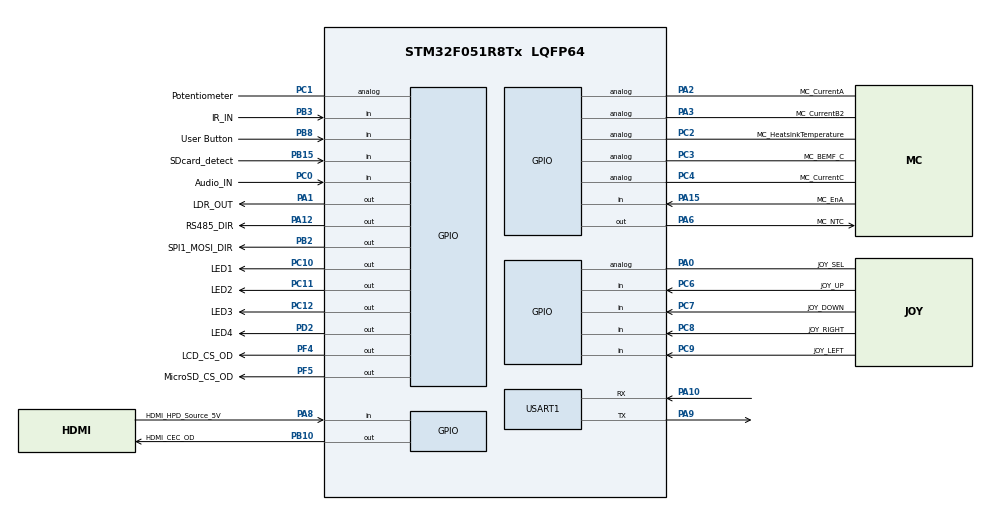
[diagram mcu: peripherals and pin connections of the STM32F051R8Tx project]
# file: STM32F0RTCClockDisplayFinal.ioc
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Mcu.Family=STM32F0
Mcu.Name=STM32F051R8Tx
Mcu.Package=LQFP64
PA0.GPIO_Label=JOY_SEL
PA0.Signal=GPIO_Analog
PA1.GPIO_Label=LDR_OUT
PA1.Signal=GPIO_Output
PA10.Mode=Asynchronous
PA10.Signal=USART1_RX
PA11.Signal=USART1_CTS
PA12.GPIO_Label=RS485_DIR
PA12.Signal=GPIO_Output
PA13.Mode=Serial_Wire
PA13.Signal=SYS_SWDIO
PA14.Mode=Serial_Wire
PA14.Signal=SYS_SWCLK
PA15.GPIO_Label=MC_EnA
PA15.Signal=GPIO_Input
PA2.GPIO_Label=MC_CurrentA
PA2.Signal=GPIO_Analog
PA3.GPIO_Label=MC_CurrentB2
PA3.Signal=GPIO_Analog
PA4.GPIO_Label=Audio_OUT
PA4.Signal=COMP_DAC11_group
PA5.Signal=SPI1_SCK
PA6.GPIO_Label=MC_NTC
PA6.Signal=GPIO_Output
PA7.Signal=SPI1_MOSI
PA8.GPIO_Label=HDMI_HPD_Source_5V
PA8.Signal=GPIO_Input
PA9.Mode=Asynchronous
PA9.Signal=USART1_TX
PB0.Signal=TSC_G3_IO2
PB1.GPIO_Label=MC_PFCpwm
PB1.Signal=S_TIM3_CH4
PB10.GPIO_Label=HDMI_CEC_OD
PB10.Signal=GPIO_Output
PB11.Signal=TSC_G6_IO1
PB12.Signal=TSC_G6_IO2
PB13.Signal=TSC_G6_IO3
PB14.Signal=TSC_G6_IO4
PB15.GPIO_Label=SDcard_detect
PB15.Signal=GPIO_Input
PB2.GPIO_Label=SPI1_MOSI_DIR
PB2.Signal=GPIO_Output
PB3.GPIO_Label=IR_IN
PB3.Signal=GPIO_Input
PB4.Signal=SPI1_MISO
PB5.GPIO_Pu=GPIO_PULLUP
PB5.Signal=I2C1_SMBA
PB8.GPIO_Label=User Button
PB8.Signal=GPIO_Input
PB9.Signal=IR_OUT
PC0.GPIO_Label=Audio_IN
PC0.Signal=GPIO_Input
PC1.GPIO_Label=Potentiometer
PC1.Signal=GPIO_Analog
PC10.GPIO_Label=LED1
PC10.Signal=GPIO_Output
PC11.GPIO_Label=LED2
PC11.Signal=GPIO_Output
PC12.GPIO_Label=LED3
PC12.Signal=GPIO_Output
PC13.Signal=SYS_WKUP2
PC14-OSC32_IN.Mode=LSE-External-Oscillator
PC14-OSC32_IN.Signal=RCC_OSC32_IN
PC15-OSC32_OUT.Mode=LSE-External-Oscillator
PC15-OSC32_OUT.Signal=RCC_OSC32_OUT
PC2.GPIO_Label=MC_HeatsinkTemperature
PC2.Signal=GPIO_Analog
PC3.GPIO_Label=MC_BEMF_C
PC3.Signal=GPIO_Analog
PC4.GPIO_Label=MC_CurrentC
PC4.Signal=GPIO_Analog
PC5.Signal=TSC_G3_IO1
PC6.GPIO_Label=JOY_UP
PC6.Signal=GPIO_Input
PC7.GPIO_Label=JOY_DOWN
PC7.Signal=GPIO_Input
PC8.GPIO_Label=JOY_RIGHT
PC8.Signal=GPIO_Input
PC9.GPIO_Label=JOY_LEFT
PC9.Signal=GPIO_Input
PD2.GPIO_Label=LED4
PD2.Signal=GPIO_Output
PF0-OSC_IN.Mode=HSE-External-Oscillator
PF0-OSC_IN.Signal=RCC_OSC_IN
PF1-OSC_OUT.Mode=HSE-External-Oscillator
PF1-OSC_OUT.Signal=RCC_OSC_OUT
PF4.GPIO_Label=LCD_CS_OD
PF4.Signal=GPIO_Output
PF5.GPIO_Label=MicroSD_CS_OD
PF5.Signal=GPIO_Output
PF7.GPIO_Pu=GPIO_PULLUP
PF7.Signal=I2C2_SDA
ProjectManager.HeapSize=0x200
ProjectManager.StackSize=0x400
ProjectManager.TargetToolchain=STM32CubeIDE
RCC.AHBCLKDivider=RCC_SYSCLK_DIV2
RCC.AHBFreq_Value=8000000
RCC.APB1Freq_Value=8000000
RCC.APB1TimFreq_Value=8000000
RCC.HCLKFreq_Value=8000000
RCC.PLLMUL=RCC_PLL_MUL4
RCC.SYSCLKFreq_VALUE=16000000
RCC.SYSCLKSource=RCC_SYSCLKSOURCE_PLLCLK
RTC.Month=RTC_MONTH_APRIL
RTC.Year=23
SH.COMP_DAC11_group.0=DAC1_OUT1
SH.S_TIM3_CH4.0=TIM3_CH4
USART1.VirtualMode-Asynchronous=VM_ASYNC
VP_RTC_VS_RTC_Activate.Mode=RTC_Enabled
VP_RTC_VS_RTC_Calendar.Mode=RTC_Calendar
board=STM320518-EVAL

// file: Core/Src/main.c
/* USER CODE BEGIN Header */
/**
  ******************************************************************************
  * @file           : main.c
  * @brief          : Main program body
  ******************************************************************************
  * @attention
  *
  * Copyright (c) 2023 STMicroelectronics.
  * All rights reserved.
  *
  * This software is licensed under terms that can be found in the LICENSE file
  * in the root directory of this software component.
  * If no LICENSE file comes with this software, it is provided AS-IS.
  *
  ******************************************************************************
  */
/* USER CODE END Header */
#include "main.h"

/* USER CODE BEGIN Includes */
#include <stdio.h>
#include <string.h>
/* USER CODE END Includes */

/* USER CODE BEGIN PTD */
char time[30];
char date[30];
/* USER CODE END PTD */
RTC_TimeTypeDef sTime;
  RTC_DateTypeDef sDate;

RTC_HandleTypeDef hrtc;

UART_HandleTypeDef huart1;

void SystemClock_Config(void);
static void MX_GPIO_Init(void);
static void MX_RTC_Init(void);
static void MX_USART1_UART_Init(void);

int main(void)
{

  /* MCU Configuration--------------------------------------------------------*/

  /* Reset of all peripherals, Initializes the Flash interface and the Systick. */
  HAL_Init();

  /* Configure the system clock */
  SystemClock_Config();

  /* Initialize all configured peripherals */
  MX_GPIO_Init();
  MX_RTC_Init();
  MX_USART1_UART_Init();

  /* Infinite loop */
  while (1)
  {
HAL_RTC_GetDate(&hrtc, &sDate, RTC_FORMAT_BIN);
HAL_RTC_GetTime(&hrtc, &sTime, RTC_FORMAT_BIN);

    /* USER CODE BEGIN 3 */
sprintf(time,"Current Time: %02d.%02d.%02d.%02lu\r\n",sTime.Hours,sTime.Minutes,sTime.Seconds, sTime.SubSeconds);

HAL_UART_Transmit(&huart1, (uint8_t *)date, sizeof(date), 300);
HAL_UART_Transmit(&huart1, (uint8_t *)time, sizeof(time), 300);
HAL_Delay(1000);
  }
  /* USER CODE END 3 */
}

void SystemClock_Config(void)
{
  RCC_OscInitTypeDef RCC_OscInitStruct = {0};
  RCC_ClkInitTypeDef RCC_ClkInitStruct = {0};
  RCC_PeriphCLKInitTypeDef PeriphClkInit = {0};

  /** Initializes the RCC Oscillators according to the specified parameters
  * in the RCC_OscInitTypeDef structure.
  */
  RCC_OscInitStruct.OscillatorType = RCC_OSCILLATORTYPE_HSI|RCC_OSCILLATORTYPE_LSI;
  RCC_OscInitStruct.HSIState = RCC_HSI_ON;
  RCC_OscInitStruct.HSICalibrationValue = RCC_HSICALIBRATION_DEFAULT;
  RCC_OscInitStruct.LSIState = RCC_LSI_ON;
  RCC_OscInitStruct.PLL.PLLState = RCC_PLL_ON;
  RCC_OscInitStruct.PLL.PLLSource = RCC_PLLSOURCE_HSI;
  RCC_OscInitStruct.PLL.PLLMUL = RCC_PLL_MUL12;
  RCC_OscInitStruct.PLL.PREDIV = RCC_PREDIV_DIV1;
  if (HAL_RCC_OscConfig(&RCC_OscInitStruct) != HAL_OK)
  {
    Error_Handler();
  }

  /** Initializes the CPU, AHB and APB buses clocks
  */
  RCC_ClkInitStruct.ClockType = RCC_CLOCKTYPE_HCLK|RCC_CLOCKTYPE_SYSCLK
                              |RCC_CLOCKTYPE_PCLK1;
  RCC_ClkInitStruct.SYSCLKSource = RCC_SYSCLKSOURCE_PLLCLK;
  RCC_ClkInitStruct.AHBCLKDivider = RCC_SYSCLK_DIV1;
  RCC_ClkInitStruct.APB1CLKDivider = RCC_HCLK_DIV1;

  if (HAL_RCC_ClockConfig(&RCC_ClkInitStruct, FLASH_LATENCY_1) != HAL_OK)
  {
    Error_Handler();
  }
  PeriphClkInit.PeriphClockSelection = RCC_PERIPHCLK_USART1|RCC_PERIPHCLK_RTC;
  PeriphClkInit.Usart1ClockSelection = RCC_USART1CLKSOURCE_PCLK1;
  PeriphClkInit.RTCClockSelection = RCC_RTCCLKSOURCE_LSI;
  if (HAL_RCCEx_PeriphCLKConfig(&PeriphClkInit) != HAL_OK)
  {
    Error_Handler();
  }
}

static void MX_RTC_Init(void)
{

  RTC_TimeTypeDef sTime = {0};
  RTC_DateTypeDef sDate = {0};

  /** Initialize RTC Only
  */
  hrtc.Instance = RTC;
  hrtc.Init.HourFormat = RTC_HOURFORMAT_24;
  hrtc.Init.AsynchPrediv = 127;
  hrtc.Init.SynchPrediv = 255;
  hrtc.Init.OutPut = RTC_OUTPUT_DISABLE;
  hrtc.Init.OutPutPolarity = RTC_OUTPUT_POLARITY_HIGH;
  hrtc.Init.OutPutType = RTC_OUTPUT_TYPE_OPENDRAIN;
  if (HAL_RTC_Init(&hrtc) != HAL_OK)
  {
    Error_Handler();
  }

  /** Initialize RTC and set the Time and Date
  */
  sTime.Hours = 0x10;
  sTime.Minutes = 0x20;
  sTime.Seconds = 0x30;
  sTime.SubSeconds = 0x40;
  sTime.DayLightSaving = RTC_DAYLIGHTSAVING_NONE;
  sTime.StoreOperation = RTC_STOREOPERATION_RESET;
  if (HAL_RTC_SetTime(&hrtc, &sTime, RTC_FORMAT_BCD) != HAL_OK)
  {
    Error_Handler();
  }
  sDate.WeekDay = RTC_WEEKDAY_MONDAY;
  sDate.Month = RTC_MONTH_APRIL;
  sDate.Date = 0x1;
  sDate.Year = 0x23;

  if (HAL_RTC_SetDate(&hrtc, &sDate, RTC_FORMAT_BCD) != HAL_OK)
  {
    Error_Handler();
  }

}

static void MX_USART1_UART_Init(void)
{

  huart1.Instance = USART1;
  huart1.Init.BaudRate = 115200;
  huart1.Init.WordLength = UART_WORDLENGTH_8B;
  huart1.Init.StopBits = UART_STOPBITS_1;
  huart1.Init.Parity = UART_PARITY_NONE;
  huart1.Init.Mode = UART_MODE_TX_RX;
  huart1.Init.HwFlowCtl = UART_HWCONTROL_NONE;
  huart1.Init.OverSampling = UART_OVERSAMPLING_16;
  huart1.Init.OneBitSampling = UART_ONE_BIT_SAMPLE_DISABLE;
  huart1.AdvancedInit.AdvFeatureInit = UART_ADVFEATURE_NO_INIT;
  if (HAL_UART_Init(&huart1) != HAL_OK)
  {
    Error_Handler();
  }

}

static void MX_GPIO_Init(void)
{
  GPIO_InitTypeDef GPIO_InitStruct = {0};

  /* GPIO Ports Clock Enable */
  __HAL_RCC_GPIOC_CLK_ENABLE();
  __HAL_RCC_GPIOF_CLK_ENABLE();
  __HAL_RCC_GPIOA_CLK_ENABLE();
  __HAL_RCC_GPIOB_CLK_ENABLE();
  __HAL_RCC_GPIOD_CLK_ENABLE();

  /*Configure GPIO pin Output Level */
  HAL_GPIO_WritePin(GPIOA, LDR_OUT_Pin|MC_NTC_Pin|RS485_DIR_Pin, GPIO_PIN_RESET);

  /*Configure GPIO pin Output Level */
  HAL_GPIO_WritePin(GPIOF, LCD_CS_OD_Pin|MicroSD_CS_OD_Pin, GPIO_PIN_RESET);

  /*Configure GPIO pin Output Level */
  HAL_GPIO_WritePin(GPIOB, SPI1_MOSI_DIR_Pin|HDMI_CEC_OD_Pin, GPIO_PIN_RESET);

  /*Configure GPIO pin Output Level */
  HAL_GPIO_WritePin(GPIOC, LED1_Pin|LED2_Pin|LED3_Pin, GPIO_PIN_RESET);

  /*Configure GPIO pin Output Level */
  HAL_GPIO_WritePin(LED4_GPIO_Port, LED4_Pin, GPIO_PIN_RESET);

  /*Configure GPIO pins : Audio_IN_Pin JOY_UP_Pin JOY_DOWN_Pin JOY_RIGHT_Pin
                           JOY_LEFT_Pin */
  GPIO_InitStruct.Pin = Audio_IN_Pin|JOY_UP_Pin|JOY_DOWN_Pin|JOY_RIGHT_Pin
                          |JOY_LEFT_Pin;
  GPIO_InitStruct.Mode = GPIO_MODE_INPUT;
  GPIO_InitStruct.Pull = GPIO_NOPULL;
  HAL_GPIO_Init(GPIOC, &GPIO_InitStruct);

  /*Configure GPIO pins : Potentiometer_Pin MC_HeatsinkTemperature_Pin MC_BEMF_C_Pin MC_CurrentC_Pin */
  GPIO_InitStruct.Pin = Potentiometer_Pin|MC_HeatsinkTemperature_Pin|MC_BEMF_C_Pin|MC_CurrentC_Pin;
  GPIO_InitStruct.Mode = GPIO_MODE_ANALOG;
  GPIO_InitStruct.Pull = GPIO_NOPULL;
  HAL_GPIO_Init(GPIOC, &GPIO_InitStruct);

  /*Configure GPIO pins : JOY_SEL_Pin MC_CurrentA_Pin MC_CurrentB2_Pin Audio_OUT_Pin */
  GPIO_InitStruct.Pin = JOY_SEL_Pin|MC_CurrentA_Pin|MC_CurrentB2_Pin|Audio_OUT_Pin;
  GPIO_InitStruct.Mode = GPIO_MODE_ANALOG;
  GPIO_InitStruct.Pull = GPIO_NOPULL;
  HAL_GPIO_Init(GPIOA, &GPIO_InitStruct);

  /*Configure GPIO pins : LDR_OUT_Pin MC_NTC_Pin RS485_DIR_Pin */
  GPIO_InitStruct.Pin = LDR_OUT_Pin|MC_NTC_Pin|RS485_DIR_Pin;
  GPIO_InitStruct.Mode = GPIO_MODE_OUTPUT_PP;
  GPIO_InitStruct.Pull = GPIO_NOPULL;
  GPIO_InitStruct.Speed = GPIO_SPEED_FREQ_LOW;
  HAL_GPIO_Init(GPIOA, &GPIO_InitStruct);

  /*Configure GPIO pins : LCD_CS_OD_Pin MicroSD_CS_OD_Pin */
  GPIO_InitStruct.Pin = LCD_CS_OD_Pin|MicroSD_CS_OD_Pin;
  GPIO_InitStruct.Mode = GPIO_MODE_OUTPUT_PP;
  GPIO_InitStruct.Pull = GPIO_NOPULL;
  GPIO_InitStruct.Speed = GPIO_SPEED_FREQ_LOW;
  HAL_GPIO_Init(GPIOF, &GPIO_InitStruct);

  /*Configure GPIO pins : PA5 PA7 */
  GPIO_InitStruct.Pin = GPIO_PIN_5|GPIO_PIN_7;
  GPIO_InitStruct.Mode = GPIO_MODE_AF_PP;
  GPIO_InitStruct.Pull = GPIO_NOPULL;
  GPIO_InitStruct.Speed = GPIO_SPEED_FREQ_HIGH;
  GPIO_InitStruct.Alternate = GPIO_AF0_SPI1;
  HAL_GPIO_Init(GPIOA, &GPIO_InitStruct);

  /*Configure GPIO pin : PC5 */
  GPIO_InitStruct.Pin = GPIO_PIN_5;
  GPIO_InitStruct.Mode = GPIO_MODE_AF_PP;
  GPIO_InitStruct.Pull = GPIO_NOPULL;
  GPIO_InitStruct.Speed = GPIO_SPEED_FREQ_LOW;
  HAL_GPIO_Init(GPIOC, &GPIO_InitStruct);

  /*Configure GPIO pins : PB0 PB11 PB12 PB13
                           PB14 */
  GPIO_InitStruct.Pin = GPIO_PIN_0|GPIO_PIN_11|GPIO_PIN_12|GPIO_PIN_13
                          |GPIO_PIN_14;
  GPIO_InitStruct.Mode = GPIO_MODE_AF_PP;
  GPIO_InitStruct.Pull = GPIO_NOPULL;
  GPIO_InitStruct.Speed = GPIO_SPEED_FREQ_LOW;
  GPIO_InitStruct.Alternate = GPIO_AF3_TSC;
  HAL_GPIO_Init(GPIOB, &GPIO_InitStruct);

  /*Configure GPIO pin : MC_PFCpwm_Pin */
  GPIO_InitStruct.Pin = MC_PFCpwm_Pin;
  GPIO_InitStruct.Mode = GPIO_MODE_AF_PP;
  GPIO_InitStruct.Pull = GPIO_NOPULL;
  GPIO_InitStruct.Speed = GPIO_SPEED_FREQ_LOW;
  GPIO_InitStruct.Alternate = GPIO_AF1_TIM3;
  HAL_GPIO_Init(MC_PFCpwm_GPIO_Port, &GPIO_InitStruct);

  /*Configure GPIO pins : SPI1_MOSI_DIR_Pin HDMI_CEC_OD_Pin */
  GPIO_InitStruct.Pin = SPI1_MOSI_DIR_Pin|HDMI_CEC_OD_Pin;
  GPIO_InitStruct.Mode = GPIO_MODE_OUTPUT_PP;
  GPIO_InitStruct.Pull = GPIO_NOPULL;
  GPIO_InitStruct.Speed = GPIO_SPEED_FREQ_LOW;
  HAL_GPIO_Init(GPIOB, &GPIO_InitStruct);

  /*Configure GPIO pins : SDcard_detect_Pin IR_IN_Pin User_Button_Pin */
  GPIO_InitStruct.Pin = SDcard_detect_Pin|IR_IN_Pin|User_Button_Pin;
  GPIO_InitStruct.Mode = GPIO_MODE_INPUT;
  GPIO_InitStruct.Pull = GPIO_NOPULL;
  HAL_GPIO_Init(GPIOB, &GPIO_InitStruct);

  /*Configure GPIO pins : HDMI_HPD_Source_5V_Pin MC_EnA_Pin */
  GPIO_InitStruct.Pin = HDMI_HPD_Source_5V_Pin|MC_EnA_Pin;
  GPIO_InitStruct.Mode = GPIO_MODE_INPUT;
  GPIO_InitStruct.Pull = GPIO_NOPULL;
  HAL_GPIO_Init(GPIOA, &GPIO_InitStruct);

  /*Configure GPIO pin : PF7 */
  GPIO_InitStruct.Pin = GPIO_PIN_7;
  GPIO_InitStruct.Mode = GPIO_MODE_AF_OD;
  GPIO_InitStruct.Pull = GPIO_PULLUP;
  GPIO_InitStruct.Speed = GPIO_SPEED_FREQ_HIGH;
  HAL_GPIO_Init(GPIOF, &GPIO_InitStruct);

  /*Configure GPIO pins : LED1_Pin LED2_Pin LED3_Pin */
  GPIO_InitStruct.Pin = LED1_Pin|LED2_Pin|LED3_Pin;
  GPIO_InitStruct.Mode = GPIO_MODE_OUTPUT_PP;
  GPIO_InitStruct.Pull = GPIO_NOPULL;
  GPIO_InitStruct.Speed = GPIO_SPEED_FREQ_LOW;
  HAL_GPIO_Init(GPIOC, &GPIO_InitStruct);

  /*Configure GPIO pin : LED4_Pin */
  GPIO_InitStruct.Pin = LED4_Pin;
  GPIO_InitStruct.Mode = GPIO_MODE_OUTPUT_PP;
  GPIO_InitStruct.Pull = GPIO_NOPULL;
  GPIO_InitStruct.Speed = GPIO_SPEED_FREQ_LOW;
  HAL_GPIO_Init(LED4_GPIO_Port, &GPIO_InitStruct);

  /*Configure GPIO pin : PB4 */
  GPIO_InitStruct.Pin = GPIO_PIN_4;
  GPIO_InitStruct.Mode = GPIO_MODE_AF_PP;
  GPIO_InitStruct.Pull = GPIO_NOPULL;
  GPIO_InitStruct.Speed = GPIO_SPEED_FREQ_HIGH;
  GPIO_InitStruct.Alternate = GPIO_AF0_SPI1;
  HAL_GPIO_Init(GPIOB, &GPIO_InitStruct);

  /*Configure GPIO pin : PB5 */
  GPIO_InitStruct.Pin = GPIO_PIN_5;
  GPIO_InitStruct.Mode = GPIO_MODE_AF_OD;
  GPIO_InitStruct.Pull = GPIO_PULLUP;
  GPIO_InitStruct.Speed = GPIO_SPEED_FREQ_HIGH;
  GPIO_InitStruct.Alternate = GPIO_AF3_I2C1;
  HAL_GPIO_Init(GPIOB, &GPIO_InitStruct);

  /*Configure GPIO pin : PB9 */
  GPIO_InitStruct.Pin = GPIO_PIN_9;
  GPIO_InitStruct.Mode = GPIO_MODE_AF_PP;
  GPIO_InitStruct.Pull = GPIO_NOPULL;
  GPIO_InitStruct.Speed = GPIO_SPEED_FREQ_HIGH;
  GPIO_InitStruct.Alternate = GPIO_AF0_IR;
  HAL_GPIO_Init(GPIOB, &GPIO_InitStruct);

}

void Error_Handler(void)
{
  __disable_irq();
  while (1)
  {
  }
}
